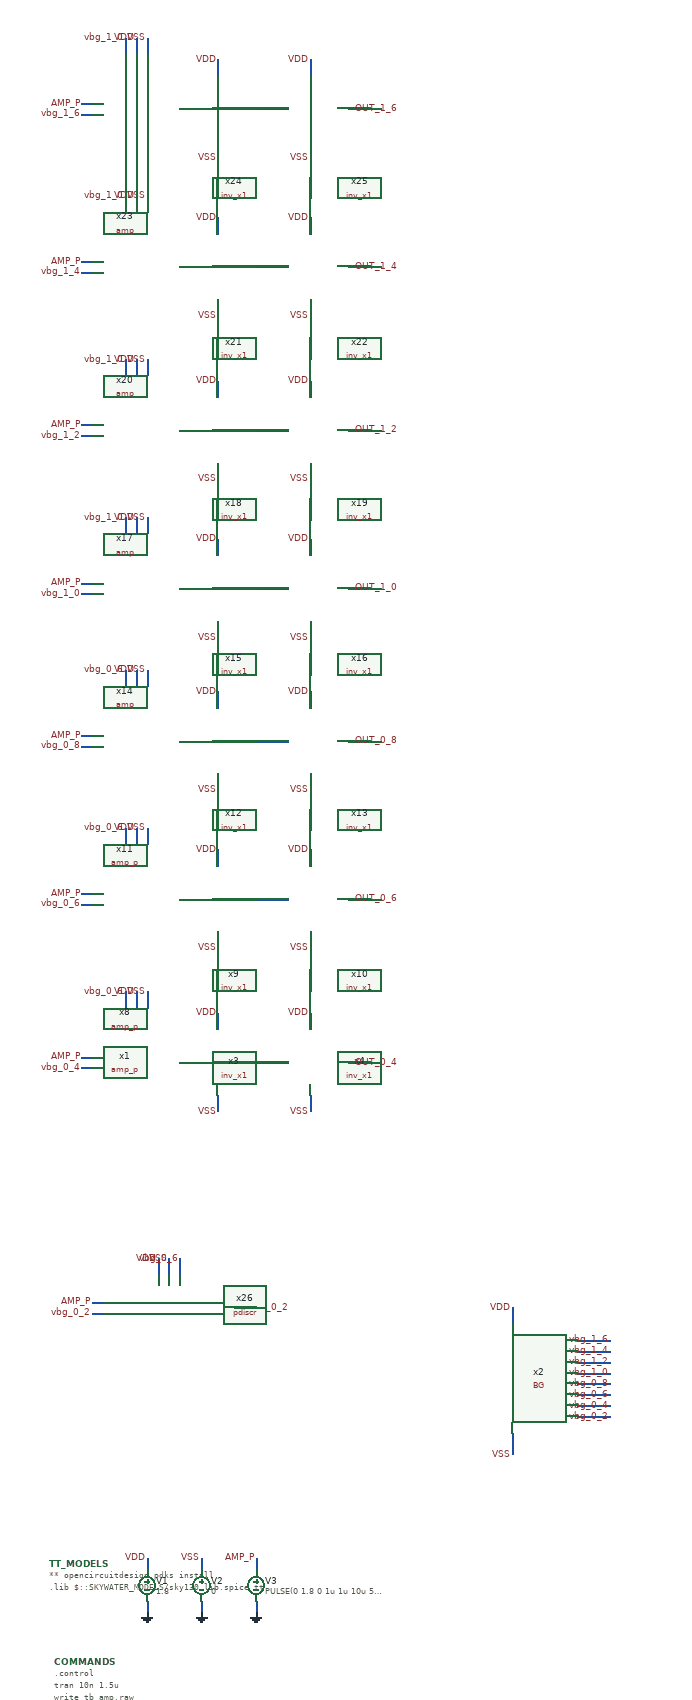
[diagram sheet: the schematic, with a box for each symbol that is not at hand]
v {xschem version=3.4.5 file_version=1.2
}
G {}
K {}
V {}
S {}
E {}
B 2 560 -400 1360 0 {flags=graph
y1=-0.1824934
y2=1.8853497
ypos1=0
ypos2=2

subdivy=1
unity=1
x1=-3.4042246e-08
x2=1.0520994e-06
divx=5
subdivx=1
xlabmag=1.0
ylabmag=1.0


dataset=-1
unitx=1
logx=0
logy=0


divy=10
color="4 4 5 5 8 8 10 10 7 7 11 11 8 8 9 9 8"
node="out_0_2
vbg_0_2
out_0_4
vbg_0_4
out_0_6
vbg_0_6
out_0_8
vbg_0_8
out_1_0
vbg_1_0
out_1_2
vbg_1_2
out_1_4
vbg_1_4
out_1_6
vbg_1_6
amp_p"}
N 200 -220 200 -200 {
lab=GND}
N 300 -220 300 -200 {
lab=GND}
N 200 -300 200 -280 {
lab=VDD}
N 300 -300 300 -280 {
lab=VSS}
N 870 -530 870 -500 {
lab=VSS}
N 870 -500 870 -490 {
lab=VSS}
N 990 -700 1030 -700 {
lab=vbg_1_6}
N 990 -680 1030 -680 {
lab=vbg_1_4}
N 1040 -680 1050 -680 {
lab=vbg_1_4}
N 1030 -680 1040 -680 {
lab=vbg_1_4}
N 1040 -700 1050 -700 {
lab=vbg_1_6}
N 1030 -700 1040 -700 {
lab=vbg_1_6}
N 990 -660 1030 -660 {
lab=vbg_1_2}
N 1040 -660 1050 -660 {
lab=vbg_1_2}
N 1030 -660 1040 -660 {
lab=vbg_1_2}
N 990 -640 1030 -640 {
lab=vbg_1_0}
N 1040 -640 1050 -640 {
lab=vbg_1_0}
N 1030 -640 1040 -640 {
lab=vbg_1_0}
N 990 -620 1030 -620 {
lab=vbg_0_8}
N 1040 -620 1050 -620 {
lab=vbg_0_8}
N 1030 -620 1040 -620 {
lab=vbg_0_8}
N 990 -600 1030 -600 {
lab=vbg_0_6}
N 1040 -600 1050 -600 {
lab=vbg_0_6}
N 1030 -600 1040 -600 {
lab=vbg_0_6}
N 990 -580 1030 -580 {
lab=vbg_0_4}
N 1040 -580 1050 -580 {
lab=vbg_0_4}
N 1030 -580 1040 -580 {
lab=vbg_0_4}
N 990 -560 1030 -560 {
lab=vbg_0_2}
N 1040 -560 1050 -560 {
lab=vbg_0_2}
N 1030 -560 1040 -560 {
lab=vbg_0_2}
N 870 -760 870 -730 {
lab=VDD}
N 400 -220 400 -200 {
lab=GND}
N 400 -300 400 -280 {
lab=AMP_P}
N 260 -850 260 -820 {
lab=vbg_0_6}
N 220 -850 220 -820 {
lab=VDD}
N 240 -850 240 -820 {
lab=VSS}
N 100 -770 120 -770 {
lab=AMP_P}
N 100 -750 120 -750 {
lab=vbg_0_2}
N 360 -760 400 -760 {
lab=OUT_0_2}
N 160 -1340 160 -1310 {
lab=vbg_0_6}
N 180 -1340 180 -1310 {
lab=VDD}
N 200 -1340 200 -1310 {
lab=VSS}
N 80 -1220 100 -1220 {
lab=AMP_P}
N 80 -1200 100 -1200 {
lab=vbg_0_4}
N 260 -1210 290 -1210 {
lab=#net1}
N 330 -1150 330 -1120 {
lab=VSS}
N 330 -1300 330 -1270 {
lab=VDD}
N 430 -1210 460 -1210 {
lab=#net2}
N 570 -1210 610 -1210 {
lab=OUT_0_4}
N 500 -1150 500 -1120 {
lab=VSS}
N 500 -1300 500 -1270 {
lab=VDD}
N 400 -1210 430 -1210 {
lab=#net2}
N 160 -1640 160 -1610 {
lab=vbg_0_6}
N 180 -1640 180 -1610 {
lab=VDD}
N 200 -1640 200 -1610 {
lab=VSS}
N 80 -1520 100 -1520 {
lab=AMP_P}
N 80 -1500 100 -1500 {
lab=vbg_0_6}
N 260 -1510 290 -1510 {
lab=#net3}
N 330 -1450 330 -1420 {
lab=VSS}
N 330 -1600 330 -1570 {
lab=VDD}
N 430 -1510 460 -1510 {
lab=#net4}
N 570 -1510 610 -1510 {
lab=OUT_0_6}
N 500 -1450 500 -1420 {
lab=VSS}
N 500 -1600 500 -1570 {
lab=VDD}
N 400 -1510 430 -1510 {
lab=#net4}
N 160 -1930 160 -1900 {
lab=vbg_0_6}
N 180 -1930 180 -1900 {
lab=VDD}
N 200 -1930 200 -1900 {
lab=VSS}
N 80 -1810 100 -1810 {
lab=AMP_P}
N 80 -1790 100 -1790 {
lab=vbg_0_8}
N 260 -1800 290 -1800 {
lab=#net5}
N 330 -1740 330 -1710 {
lab=VSS}
N 330 -1890 330 -1860 {
lab=VDD}
N 430 -1800 460 -1800 {
lab=#net6}
N 570 -1800 610 -1800 {
lab=OUT_0_8}
N 500 -1740 500 -1710 {
lab=VSS}
N 500 -1890 500 -1860 {
lab=VDD}
N 400 -1800 430 -1800 {
lab=#net6}
N 160 -2210 160 -2180 {
lab=vbg_1_0}
N 180 -2210 180 -2180 {
lab=VDD}
N 200 -2210 200 -2180 {
lab=VSS}
N 80 -2090 100 -2090 {
lab=AMP_P}
N 80 -2070 100 -2070 {
lab=vbg_1_0}
N 260 -2080 290 -2080 {
lab=#net7}
N 330 -2020 330 -1990 {
lab=VSS}
N 330 -2170 330 -2140 {
lab=VDD}
N 430 -2080 460 -2080 {
lab=#net8}
N 570 -2080 610 -2080 {
lab=OUT_1_0}
N 500 -2020 500 -1990 {
lab=VSS}
N 500 -2170 500 -2140 {
lab=VDD}
N 400 -2080 430 -2080 {
lab=#net8}
N 160 -2500 160 -2470 {
lab=vbg_1_0}
N 180 -2500 180 -2470 {
lab=VDD}
N 200 -2500 200 -2470 {
lab=VSS}
N 80 -2380 100 -2380 {
lab=AMP_P}
N 80 -2360 100 -2360 {
lab=vbg_1_2}
N 260 -2370 290 -2370 {
lab=#net9}
N 330 -2310 330 -2280 {
lab=VSS}
N 330 -2460 330 -2430 {
lab=VDD}
N 430 -2370 460 -2370 {
lab=#net10}
N 570 -2370 610 -2370 {
lab=OUT_1_2}
N 500 -2310 500 -2280 {
lab=VSS}
N 500 -2460 500 -2430 {
lab=VDD}
N 400 -2370 430 -2370 {
lab=#net10}
N 160 -2800 160 -2770 {
lab=vbg_1_0}
N 180 -2800 180 -2770 {
lab=VDD}
N 200 -2800 200 -2770 {
lab=VSS}
N 80 -2680 100 -2680 {
lab=AMP_P}
N 80 -2660 100 -2660 {
lab=vbg_1_4}
N 260 -2670 290 -2670 {
lab=#net11}
N 330 -2610 330 -2580 {
lab=VSS}
N 330 -2760 330 -2730 {
lab=VDD}
N 430 -2670 460 -2670 {
lab=#net12}
N 570 -2670 610 -2670 {
lab=OUT_1_4}
N 500 -2610 500 -2580 {
lab=VSS}
N 500 -2760 500 -2730 {
lab=VDD}
N 400 -2670 430 -2670 {
lab=#net12}
N 160 -3090 160 -3060 {
lab=vbg_1_0}
N 180 -3090 180 -3060 {
lab=VDD}
N 200 -3090 200 -3060 {
lab=VSS}
N 80 -2970 100 -2970 {
lab=AMP_P}
N 80 -2950 100 -2950 {
lab=vbg_1_6}
N 260 -2960 290 -2960 {
lab=#net13}
N 330 -2900 330 -2870 {
lab=VSS}
N 330 -3050 330 -3020 {
lab=VDD}
N 430 -2960 460 -2960 {
lab=#net14}
N 570 -2960 610 -2960 {
lab=OUT_1_6}
N 500 -2900 500 -2870 {
lab=VSS}
N 500 -3050 500 -3020 {
lab=VDD}
N 400 -2960 430 -2960 {
lab=#net14}
C {devices/launcher.sym} 90 -360 0 0 {name=h17 
descr="Load waves" 
tclcommand="
xschem raw_read $netlist_dir/[file tail [file rootname [xschem get current_name]]].raw tran

"
}
C {devices/code.sym} 20 -290 0 0 {name=TT_MODELS
only_toplevel=true
format="tcleval( @value )"
value="
** opencircuitdesign pdks install
.lib $::SKYWATER_MODELS/sky130.lib.spice tt

"
spice_ignore=false}
C {devices/vsource.sym} 200 -250 0 0 {name=V1 value=1.8 savecurrent=false}
C {devices/vsource.sym} 300 -250 0 0 {name=V2 value=0 savecurrent=false}
C {devices/gnd.sym} 300 -200 0 0 {name=l1 lab=GND}
C {devices/gnd.sym} 200 -200 0 0 {name=l2 lab=GND}
C {devices/lab_wire.sym} 200 -300 0 0 {name=p5 sig_type=std_logic lab=VDD
}
C {devices/lab_wire.sym} 300 -300 0 0 {name=p6 sig_type=std_logic lab=VSS
}
C {devices/simulator_commands_shown.sym} 30 -110 0 0 {name=COMMANDS
simulator=ngspice
only_toplevel=false 
value="
.control
tran 10n 1.5u
write tb_amp.raw
.endc
"}
C {devices/lab_wire.sym} 870 -490 0 0 {name=p13 sig_type=std_logic lab=VSS}
C {devices/lab_wire.sym} 1050 -700 0 0 {name=p1 sig_type=std_logic lab=vbg_1_6}
C {devices/lab_wire.sym} 1050 -680 0 0 {name=p2 sig_type=std_logic lab=vbg_1_4}
C {devices/lab_wire.sym} 1050 -660 0 0 {name=p3 sig_type=std_logic lab=vbg_1_2}
C {devices/lab_wire.sym} 1050 -640 0 0 {name=p4 sig_type=std_logic lab=vbg_1_0}
C {devices/lab_wire.sym} 1050 -620 0 0 {name=p7 sig_type=std_logic lab=vbg_0_8}
C {devices/lab_wire.sym} 1050 -600 0 0 {name=p8 sig_type=std_logic lab=vbg_0_6}
C {devices/lab_wire.sym} 1050 -580 0 0 {name=p10 sig_type=std_logic lab=vbg_0_4}
C {devices/lab_wire.sym} 1050 -560 0 0 {name=p14 sig_type=std_logic lab=vbg_0_2}
C {BG.sym} 840 -630 0 0 {name=x2}
C {devices/lab_wire.sym} 870 -760 3 1 {name=p15 sig_type=std_logic lab=VDD}
C {devices/vsource.sym} 400 -250 0 0 {name=V3 value="PULSE(0 1.8 0 1u 1u 10u 5u)" savecurrent=false}
C {devices/gnd.sym} 400 -200 0 0 {name=l3 lab=GND}
C {devices/lab_wire.sym} 400 -300 0 0 {name=p19 sig_type=std_logic lab=AMP_P
}
C {devices/lab_wire.sym} 220 -850 3 1 {name=p20 sig_type=std_logic lab=VDD}
C {devices/lab_wire.sym} 240 -850 3 1 {name=p26 sig_type=std_logic lab=VSS}
C {devices/lab_wire.sym} 260 -850 3 1 {name=p27 sig_type=std_logic lab=vbg_0_6}
C {devices/lab_wire.sym} 100 -770 0 0 {name=p28 sig_type=std_logic lab=AMP_P}
C {devices/lab_wire.sym} 100 -750 0 0 {name=p29 sig_type=std_logic lab=vbg_0_2}
C {devices/lab_wire.sym} 380 -760 0 1 {name=p33 sig_type=std_logic lab=OUT_0_2}
C {devices/lab_wire.sym} 180 -1340 3 1 {name=p9 sig_type=std_logic lab=VDD}
C {devices/lab_wire.sym} 200 -1340 3 1 {name=p11 sig_type=std_logic lab=VSS}
C {devices/lab_wire.sym} 160 -1340 3 1 {name=p12 sig_type=std_logic lab=vbg_0_6}
C {devices/lab_wire.sym} 80 -1220 0 0 {name=p16 sig_type=std_logic lab=AMP_P}
C {devices/lab_wire.sym} 80 -1200 0 0 {name=p17 sig_type=std_logic lab=vbg_0_4}
C {inv_x1.sym} 390 -1110 0 0 {name=x3}
C {devices/lab_wire.sym} 330 -1120 3 1 {name=p18 sig_type=std_logic lab=VSS}
C {devices/lab_wire.sym} 330 -1300 3 1 {name=p21 sig_type=std_logic lab=VDD}
C {inv_x1.sym} 560 -1110 0 0 {name=x4}
C {devices/lab_wire.sym} 580 -1210 0 1 {name=p22 sig_type=std_logic lab=OUT_0_4}
C {devices/lab_wire.sym} 500 -1120 3 1 {name=p23 sig_type=std_logic lab=VSS}
C {devices/lab_wire.sym} 500 -1300 3 1 {name=p24 sig_type=std_logic lab=VDD}
C {devices/lab_wire.sym} 180 -1640 3 1 {name=p25 sig_type=std_logic lab=VDD}
C {devices/lab_wire.sym} 200 -1640 3 1 {name=p30 sig_type=std_logic lab=VSS}
C {devices/lab_wire.sym} 160 -1640 3 1 {name=p36 sig_type=std_logic lab=vbg_0_6}
C {devices/lab_wire.sym} 80 -1520 0 0 {name=p37 sig_type=std_logic lab=AMP_P}
C {devices/lab_wire.sym} 80 -1500 0 0 {name=p38 sig_type=std_logic lab=vbg_0_6}
C {inv_x1.sym} 390 -1410 0 0 {name=x9}
C {devices/lab_wire.sym} 330 -1420 3 1 {name=p39 sig_type=std_logic lab=VSS}
C {devices/lab_wire.sym} 330 -1600 3 1 {name=p40 sig_type=std_logic lab=VDD}
C {inv_x1.sym} 560 -1410 0 0 {name=x10}
C {devices/lab_wire.sym} 580 -1510 0 1 {name=p41 sig_type=std_logic lab=OUT_0_6}
C {devices/lab_wire.sym} 500 -1420 3 1 {name=p42 sig_type=std_logic lab=VSS}
C {devices/lab_wire.sym} 500 -1600 3 1 {name=p43 sig_type=std_logic lab=VDD}
C {devices/lab_wire.sym} 180 -1930 3 1 {name=p44 sig_type=std_logic lab=VDD}
C {devices/lab_wire.sym} 200 -1930 3 1 {name=p45 sig_type=std_logic lab=VSS}
C {devices/lab_wire.sym} 160 -1930 3 1 {name=p46 sig_type=std_logic lab=vbg_0_6}
C {devices/lab_wire.sym} 80 -1810 0 0 {name=p47 sig_type=std_logic lab=AMP_P}
C {devices/lab_wire.sym} 80 -1790 0 0 {name=p48 sig_type=std_logic lab=vbg_0_8}
C {inv_x1.sym} 390 -1700 0 0 {name=x12}
C {devices/lab_wire.sym} 330 -1710 3 1 {name=p49 sig_type=std_logic lab=VSS}
C {devices/lab_wire.sym} 330 -1890 3 1 {name=p50 sig_type=std_logic lab=VDD}
C {inv_x1.sym} 560 -1700 0 0 {name=x13}
C {devices/lab_wire.sym} 580 -1800 0 1 {name=p51 sig_type=std_logic lab=OUT_0_8}
C {devices/lab_wire.sym} 500 -1710 3 1 {name=p52 sig_type=std_logic lab=VSS}
C {devices/lab_wire.sym} 500 -1890 3 1 {name=p53 sig_type=std_logic lab=VDD}
C {devices/lab_wire.sym} 180 -2210 3 1 {name=p54 sig_type=std_logic lab=VDD}
C {devices/lab_wire.sym} 200 -2210 3 1 {name=p55 sig_type=std_logic lab=VSS}
C {devices/lab_wire.sym} 160 -2210 3 1 {name=p56 sig_type=std_logic lab=vbg_1_0}
C {devices/lab_wire.sym} 80 -2090 0 0 {name=p57 sig_type=std_logic lab=AMP_P}
C {devices/lab_wire.sym} 80 -2070 0 0 {name=p58 sig_type=std_logic lab=vbg_1_0}
C {amp.sym} 100 -2000 0 0 {name=x14}
C {inv_x1.sym} 390 -1980 0 0 {name=x15}
C {devices/lab_wire.sym} 330 -1990 3 1 {name=p59 sig_type=std_logic lab=VSS}
C {devices/lab_wire.sym} 330 -2170 3 1 {name=p60 sig_type=std_logic lab=VDD}
C {inv_x1.sym} 560 -1980 0 0 {name=x16}
C {devices/lab_wire.sym} 580 -2080 0 1 {name=p61 sig_type=std_logic lab=OUT_1_0}
C {devices/lab_wire.sym} 500 -1990 3 1 {name=p62 sig_type=std_logic lab=VSS}
C {devices/lab_wire.sym} 500 -2170 3 1 {name=p63 sig_type=std_logic lab=VDD}
C {devices/lab_wire.sym} 180 -2500 3 1 {name=p64 sig_type=std_logic lab=VDD}
C {devices/lab_wire.sym} 200 -2500 3 1 {name=p65 sig_type=std_logic lab=VSS}
C {devices/lab_wire.sym} 160 -2500 3 1 {name=p66 sig_type=std_logic lab=vbg_1_0}
C {devices/lab_wire.sym} 80 -2380 0 0 {name=p67 sig_type=std_logic lab=AMP_P}
C {devices/lab_wire.sym} 80 -2360 0 0 {name=p68 sig_type=std_logic lab=vbg_1_2}
C {amp.sym} 100 -2290 0 0 {name=x17}
C {inv_x1.sym} 390 -2270 0 0 {name=x18}
C {devices/lab_wire.sym} 330 -2280 3 1 {name=p69 sig_type=std_logic lab=VSS}
C {devices/lab_wire.sym} 330 -2460 3 1 {name=p70 sig_type=std_logic lab=VDD}
C {inv_x1.sym} 560 -2270 0 0 {name=x19}
C {devices/lab_wire.sym} 580 -2370 0 1 {name=p71 sig_type=std_logic lab=OUT_1_2}
C {devices/lab_wire.sym} 500 -2280 3 1 {name=p72 sig_type=std_logic lab=VSS}
C {devices/lab_wire.sym} 500 -2460 3 1 {name=p73 sig_type=std_logic lab=VDD}
C {devices/lab_wire.sym} 180 -2800 3 1 {name=p74 sig_type=std_logic lab=VDD}
C {devices/lab_wire.sym} 200 -2800 3 1 {name=p75 sig_type=std_logic lab=VSS}
C {devices/lab_wire.sym} 160 -2800 3 1 {name=p76 sig_type=std_logic lab=vbg_1_0}
C {devices/lab_wire.sym} 80 -2680 0 0 {name=p77 sig_type=std_logic lab=AMP_P}
C {devices/lab_wire.sym} 80 -2660 0 0 {name=p78 sig_type=std_logic lab=vbg_1_4}
C {amp.sym} 100 -2590 0 0 {name=x20}
C {inv_x1.sym} 390 -2570 0 0 {name=x21}
C {devices/lab_wire.sym} 330 -2580 3 1 {name=p79 sig_type=std_logic lab=VSS}
C {devices/lab_wire.sym} 330 -2760 3 1 {name=p80 sig_type=std_logic lab=VDD}
C {inv_x1.sym} 560 -2570 0 0 {name=x22}
C {devices/lab_wire.sym} 580 -2670 0 1 {name=p81 sig_type=std_logic lab=OUT_1_4}
C {devices/lab_wire.sym} 500 -2580 3 1 {name=p82 sig_type=std_logic lab=VSS}
C {devices/lab_wire.sym} 500 -2760 3 1 {name=p83 sig_type=std_logic lab=VDD}
C {devices/lab_wire.sym} 180 -3090 3 1 {name=p84 sig_type=std_logic lab=VDD}
C {devices/lab_wire.sym} 200 -3090 3 1 {name=p85 sig_type=std_logic lab=VSS}
C {devices/lab_wire.sym} 160 -3090 3 1 {name=p86 sig_type=std_logic lab=vbg_1_0}
C {devices/lab_wire.sym} 80 -2970 0 0 {name=p87 sig_type=std_logic lab=AMP_P}
C {devices/lab_wire.sym} 80 -2950 0 0 {name=p88 sig_type=std_logic lab=vbg_1_6}
C {amp.sym} 100 -2880 0 0 {name=x23}
C {inv_x1.sym} 390 -2860 0 0 {name=x24}
C {devices/lab_wire.sym} 330 -2870 3 1 {name=p89 sig_type=std_logic lab=VSS}
C {devices/lab_wire.sym} 330 -3050 3 1 {name=p90 sig_type=std_logic lab=VDD}
C {inv_x1.sym} 560 -2860 0 0 {name=x25}
C {devices/lab_wire.sym} 580 -2960 0 1 {name=p91 sig_type=std_logic lab=OUT_1_6}
C {devices/lab_wire.sym} 500 -2870 3 1 {name=p92 sig_type=std_logic lab=VSS}
C {devices/lab_wire.sym} 500 -3050 3 1 {name=p93 sig_type=std_logic lab=VDD}
C {amp_p.sym} 100 -1130 0 0 {name=x1}
C {amp_p.sym} 100 -1430 0 0 {name=x8}
C {amp_p.sym} 100 -1720 0 0 {name=x11}
C {pdiscr.sym} 120 -760 0 0 {name=x26}
